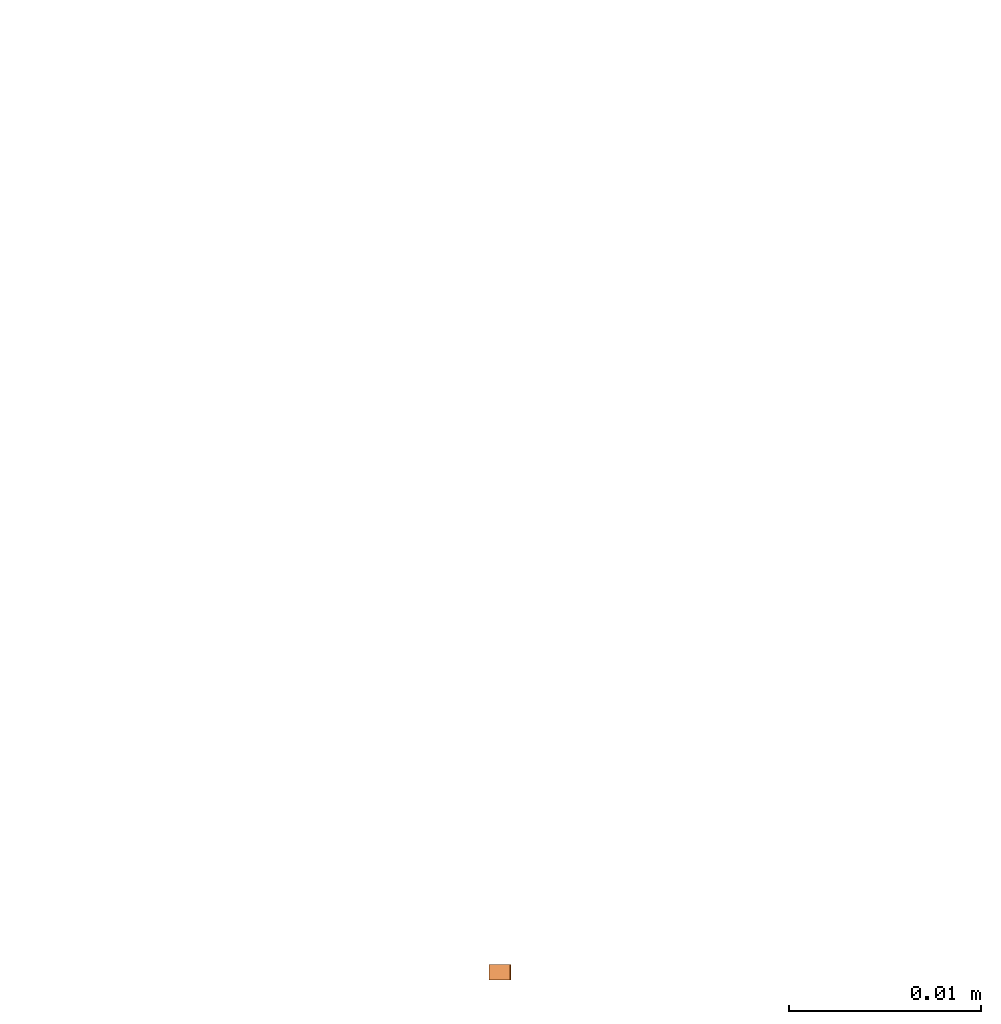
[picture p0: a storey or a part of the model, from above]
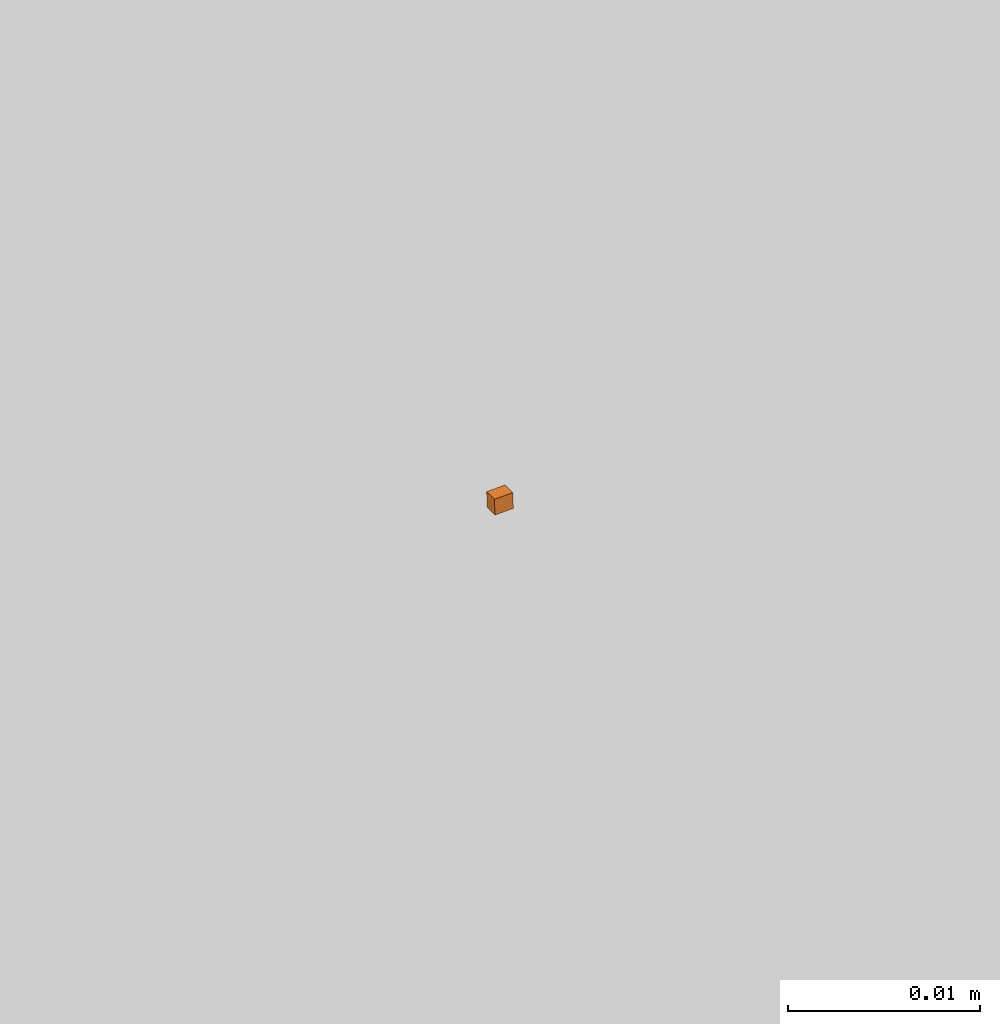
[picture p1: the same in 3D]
Properties of the parts of a building model (IFC2X3)

# File
Description: ViewDefinition [CoordinationView_V2.0]
File name: Project Number
Time: 2020-12-18T11:21:35
Written by: The EXPRESS Data Manager Version 5.02.0100.07 : 28 Aug 2013
Made in: 20190731_1515(x64) - Exporter 20.1.1.1 - Alternate UI 20.1.1.1
Comment: STEP Physical File produced by: The EXPRESS Data Manager Version 5.02.0100.07 : 28 Aug 2013 * Module: EDMstepFileFactory/EDMstandAlone * Creation date: Fri Dec 18 11:21:35 2020 * Host: LT-GBA1 * Database: C:\Users\gba\AppData\Local\Temp\88f0319a-146f-47ee-be6a-4ad0205efb3a\856d1890-13fa-4953-a40f-a62e3fcfe6da\ifc * Database version: 5507 * Database creation date: Fri Dec 18 11:21:34 2020 * Schema: IFC2X3 * Model: DataRepository.ifc * Model creation date: Fri Dec 18 11:21:34 2020 * Header model: DataRepository.ifc_HeaderModel * Header model creation date: Fri Dec 18 11:21:35 2020 * EDMuser: sdai-user * EDMgroup: sdai-group * License ID and type: 5605 : Permanent license. Expiry date: * EDMstepFileFactory options: 020000

# IfcProject, Project Number
LongName: Project Name; Phase: Project Status

# IfcSite, Default
RefLatitude: 42, 21, 31, 181945; RefLongitude: -71, -3, -24, -263305; RefElevation: 0 ft

# IfcBuilding
Pset_BuildingCommon - NumberOfStoreys: 1
Pset_ProductRequirements - Category: Project Information

# IfcBuildingStorey: Level:1/4" Head, Level 1
LongName: Level 1; Elevation: 0 ft
Pset_AirSideSystemInformation - Name: Level 1
Pset_ProductRequirements - Name: Level 1; Category: Levels

# IfcBuildingElementProxy: None 3:None, None 3:None:471101
In: Level 1
Type - Pset_ProductRequirements - Category: Parking

# IfcWallStandardCase: Basic Wall:Generic - 8", Basic Wall:Generic - 8":339185
In: Level 1
Type - PredefinedType: STANDARD; Material: Default Wall 0.666667 ft
Type - Pset_ElementShading - Roughness: 1 ft
Type - Pset_ProductRequirements - Category: Walls
Type - Pset_QuantityTakeOff - Reference: Generic - 8"
Type - Pset_ReinforcementBarPitchOfWall - Reference: Generic - 8"
Type - Pset_WallCommon - Reference: Generic - 8"; IsExternal: no
Classification: B2010 Exterior Walls (Uniformat)
Pset_QuantityTakeOff - sets with these values: 2
Pset_WallCommon - IsExternal: yes; ExtendToStructure: no; LoadBearing: no
